(* Logix 5000 project; controller Example_PLC vendor 1 type 14 code 77 rev 19.11; software revision 19.01; part 4 of 6 *)

ADD_ON_INSTRUCTION AKD_Set_Home_Mode   (* revision 2.0, ExecutePrescan, ExecuteEnableInFalse *)
// Set Homing Mode
VAR_OUTPUT
   DN : BOOL; {access Read Only, visible}   // Command Successful
   ER : BOOL; {access Read Only, visible}   // Error
END_VAR
VAR_IN_OUT
   Axis : AKD_Axis; {required}
END_VAR
VAR_INPUT
   Mode : SINT; {required}   // Home Mode:
END_VAR
VAR
   Command_Bytes : SINT[8];
   Step : DINT;
   Set_Attribute : AKD_Set_Attribute;
END_VAR

ROUTINE EnableInFalse   (* ladder *)
// EnableIn_False
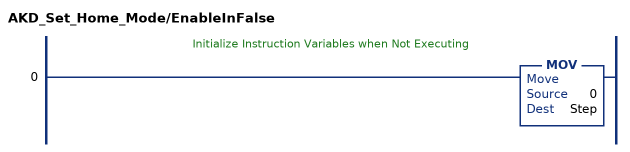
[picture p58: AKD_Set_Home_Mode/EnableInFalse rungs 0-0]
   // Initialize Instruction Variables when Not Executing
   0: MOV(0,Step);
END_ROUTINE

ROUTINE Logic   (* ladder *)
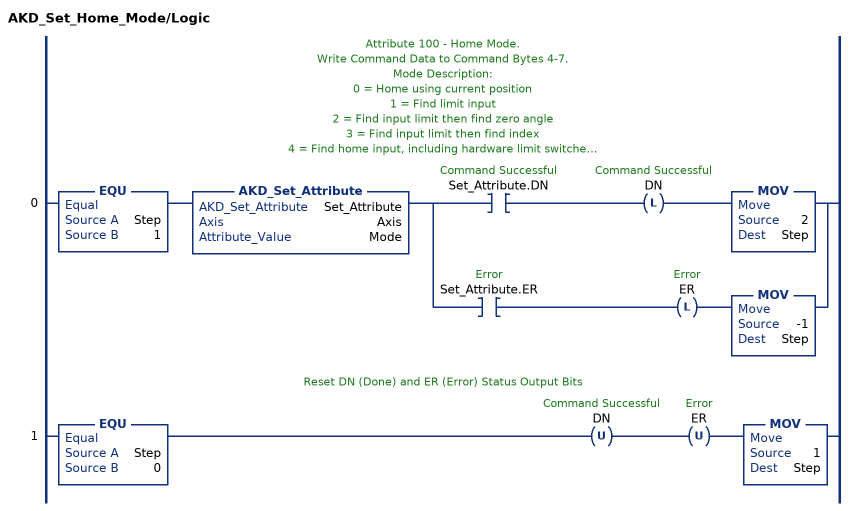
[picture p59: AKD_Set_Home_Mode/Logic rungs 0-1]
   // Attribute 100 - Home Mode.
   // Write Command Data to Command Bytes 4-7.
   // Mode Description:
   // 0 = Home using current position
   // 1 = Find limit input
   // 2 = Find input limit then find zero angle
   // 3 = Find input limit then find index
   // 4 = Find home input, including hardware limit switches
   // 5 = Find home input then find zero angle, including hardware limit switches
   // 6 = Find home input then find index, including hardware limit switches.
   // 7 = Find zero angle
   // 8 = Move until position error exceeded
   // 9 = Move until position error exceeded, then find zero angle
   // 10 = Move until position error exceeded, then find index
   // 11 = Find index signal, without any precondition
   // 12 = Homing to a home-switch, including mechanical stop detection
   0: EQU(Step,1)AKD_Set_Attribute(Set_Attribute,Axis,Mode)[XIC(Set_Attribute.DN) OTL(DN) MOV(2,Step) ,XIC(Set_Attribute.ER) OTL(ER) MOV(-1,Step) ];
   // Reset DN (Done) and ER (Error) Status Output Bits
   1: EQU(Step,0)OTU(DN)OTU(ER)MOV(1,Step);
END_ROUTINE

ROUTINE Prescan   (* ladder *)
// Prescan
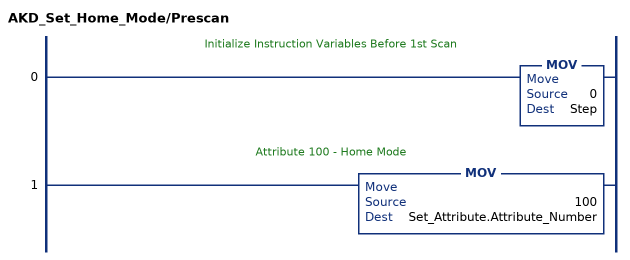
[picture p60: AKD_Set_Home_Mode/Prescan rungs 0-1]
   // Initialize Instruction Variables Before 1st Scan
   0: MOV(0,Step);
   // Attribute 100 - Home Mode
   1: MOV(100,Set_Attribute.Attribute_Number);
END_ROUTINE
END_ADD_ON_INSTRUCTION

ADD_ON_INSTRUCTION AKD_Set_Mode   (* revision 2.2, ExecutePrescan, ExecuteEnableInFalse *)
// Set Drive Mode
// Revision note:
// Recover properly from errors (previously could not recover if AKD_Set_Attribute errored)
VAR_IN_OUT
   Axis : AKD_Axis; {required}
END_VAR
VAR_INPUT
   Mode_Requested : SINT; {required}   // Drive Mode Requested (0=Position, 1=Velocity, 2=Torque)
END_VAR
VAR_OUTPUT
   DN : BOOL; {access Read Only, visible}   // Command Successfully Initiated
   ER : BOOL; {access Read Only, visible}   // Error
   Mode_Actual : SINT; {access Read Only, required}   // Drive Mode Actual (0=Position, 1=Velocity, 2=Torque)
END_VAR
VAR
   Accel_Internal : DINT;   // Scaled Accel Value for Drive
   Step : SINT;   // Sequence Step Number
   ErrorSource : SINT;   // Source of Error
   StartONS : BOOL;
   Pause_Timer : TIMER;   // Pause During Jog Command Sequence
   Get_Mode : AKD_Get_Attribute := (Attribute_Number := 3);
   Set_Mode : AKD_Set_Attribute := (Attribute_Number := 3);
   Command_Timeout : TIMER := (PRE := 100);
END_VAR

ROUTINE EnableInFalse   (* ladder *)
// EnableIn_False
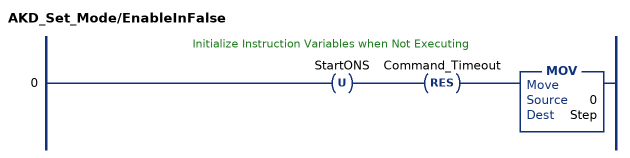
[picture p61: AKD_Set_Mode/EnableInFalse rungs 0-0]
   // Initialize Instruction Variables when Not Executing
   0: OTU(StartONS)RES(Command_Timeout)MOV(0,Step);
END_ROUTINE

ROUTINE Logic   (* ladder *)
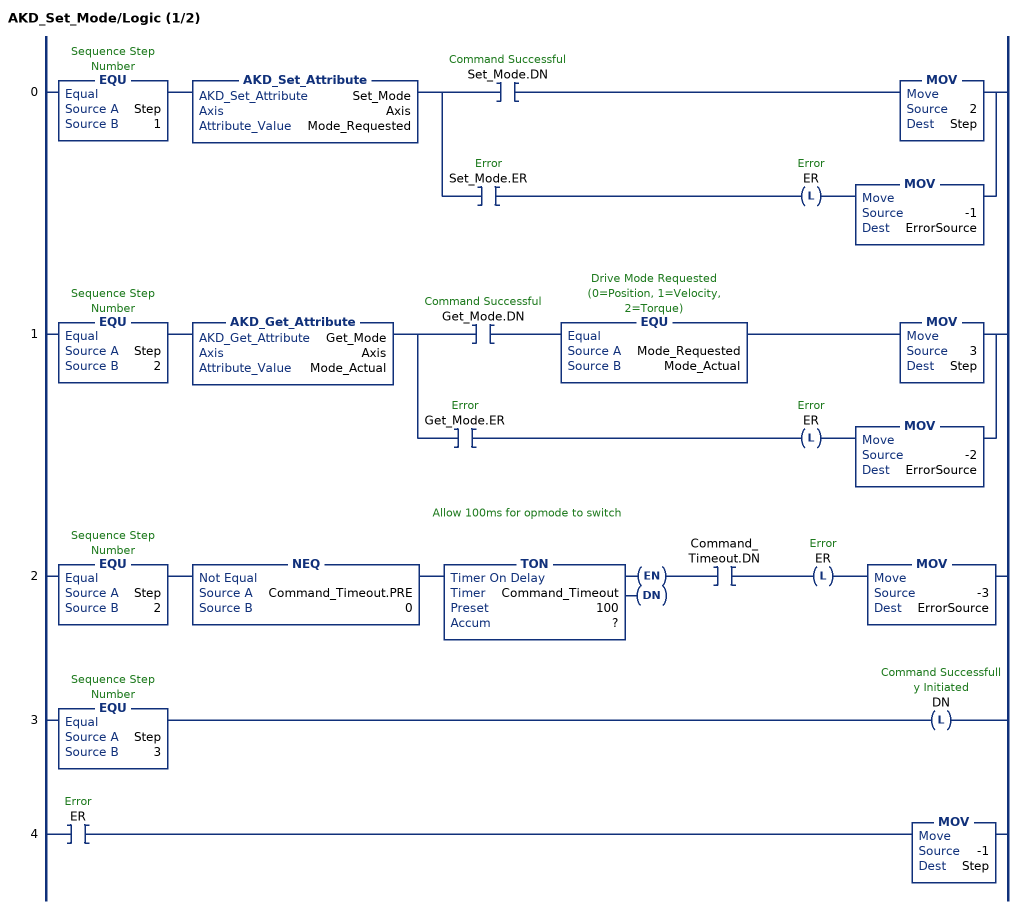
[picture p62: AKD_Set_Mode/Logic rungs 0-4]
   0: EQU(Step,1)AKD_Set_Attribute(Set_Mode,Axis,Mode_Requested)[XIC(Set_Mode.DN) MOV(2,Step) ,XIC(Set_Mode.ER) OTL(ER) MOV(-1,ErrorSource) ];
   1: EQU(Step,2)AKD_Get_Attribute(Get_Mode,Axis,Mode_Actual)[XIC(Get_Mode.DN) EQU(Mode_Requested,Mode_Actual) MOV(3,Step) ,XIC(Get_Mode.ER) OTL(ER) MOV(-2,ErrorSource) ];
   // Allow 100ms for opmode to switch
   2: EQU(Step,2)NEQ(Command_Timeout.PRE,0)TON(Command_Timeout,?,?)XIC(Command_Timeout.DN)OTL(ER)MOV(-3,ErrorSource);
   3: EQU(Step,3)OTL(DN);
   4: XIC(ER)MOV(-1,Step);
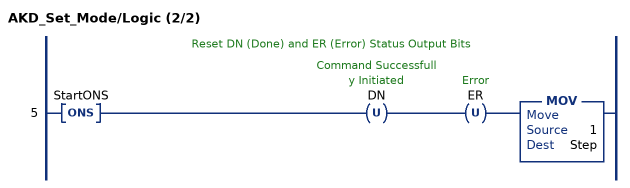
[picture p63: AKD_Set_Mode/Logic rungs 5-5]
   // Reset DN (Done) and ER (Error) Status Output Bits
   5: ONS(StartONS)OTU(DN)OTU(ER)MOV(1,Step);
END_ROUTINE

ROUTINE Prescan   (* ladder *)
// Prescan
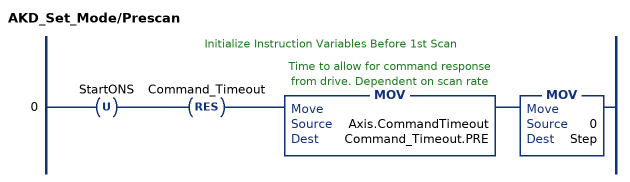
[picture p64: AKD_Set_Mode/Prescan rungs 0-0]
   // Initialize Instruction Variables Before 1st Scan
   0: OTU(StartONS)RES(Command_Timeout)MOV(Axis.CommandTimeout,Command_Timeout.PRE)MOV(0,Step);
END_ROUTINE
END_ADD_ON_INSTRUCTION

ADD_ON_INSTRUCTION AKD_Set_Parameter   (* revision 2.0, ExecutePrescan, ExecuteEnableInFalse *)
// Set Drive Parameter
VAR_OUTPUT
   DN : BOOL; {access Read Only, visible}   // Command Successful
   ER : BOOL; {access Read Only, visible}   // Error
END_VAR
VAR_IN_OUT
   Axis : AKD_Axis; {required}
END_VAR
VAR_INPUT
   Parameter_Number : INT; {visible}   // See help (F1) for parameter list.
   Parameter_Value : DINT; {required}   // Parameter Value
END_VAR
VAR
   Command_Timeout : TIMER := (PRE := 10000);   // Timeout Timer
   Command_Message_Type : SINT;   // Command Message Type
   Command_Axis_Number : SINT;   // Command Axis Number
   Step : SINT;
   Command_Bytes : SINT[8];
   OS_LoadStart : BOOL;
   Temp_Bytes : SINT[2];   // Temporary Bytes to Split into Command Bytes
END_VAR

ROUTINE EnableInFalse   (* ladder *)
// EnableIn_False
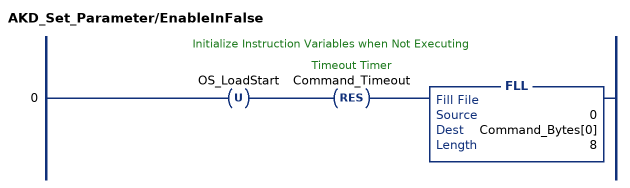
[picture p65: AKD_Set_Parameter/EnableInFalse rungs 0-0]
   // Initialize Instruction Variables when Not Executing
   0: OTU(OS_LoadStart)RES(Command_Timeout)FLL(0,Command_Bytes[0],8);
END_ROUTINE

ROUTINE Logic   (* ladder *)
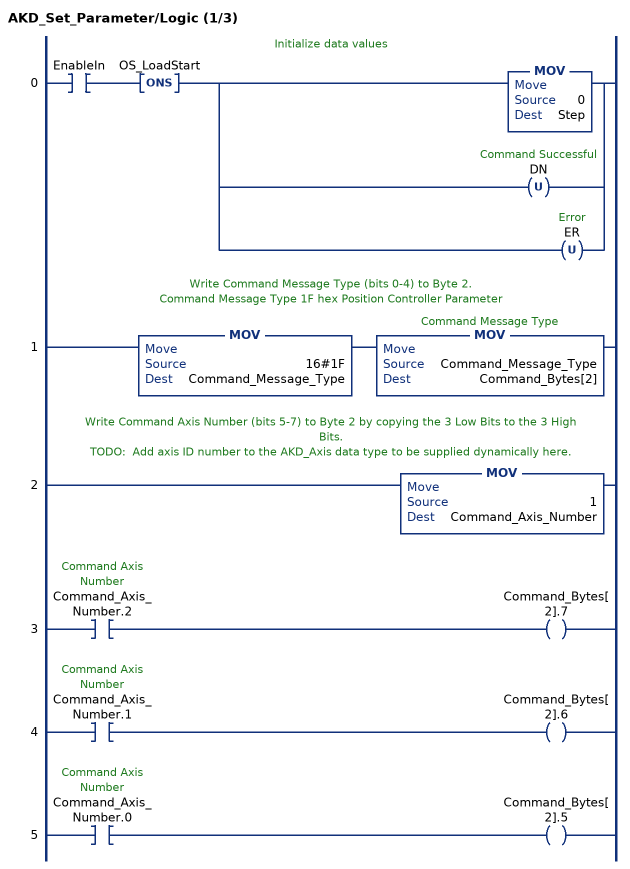
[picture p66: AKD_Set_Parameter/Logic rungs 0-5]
   // Initialize data values
   0: XIC(EnableIn)ONS(OS_LoadStart)[MOV(0,Step) ,OTU(DN) ,OTU(ER) ];
   // Write Command Message Type (bits 0-4) to Byte 2.
   // Command Message Type 1F hex Position Controller Parameter
   1: MOV(16#1F,Command_Message_Type)MOV(Command_Message_Type,Command_Bytes[2]);
   // Write Command Axis Number (bits 5-7) to Byte 2 by copying the 3 Low Bits to the 3 High Bits.
   // TODO:  Add axis ID number to the AKD_Axis data type to be supplied dynamically here.
   2: MOV(1,Command_Axis_Number);
   3: XIC(Command_Axis_Number.2)OTE(Command_Bytes[2].7);
   4: XIC(Command_Axis_Number.1)OTE(Command_Bytes[2].6);
   5: XIC(Command_Axis_Number.0)OTE(Command_Bytes[2].5);
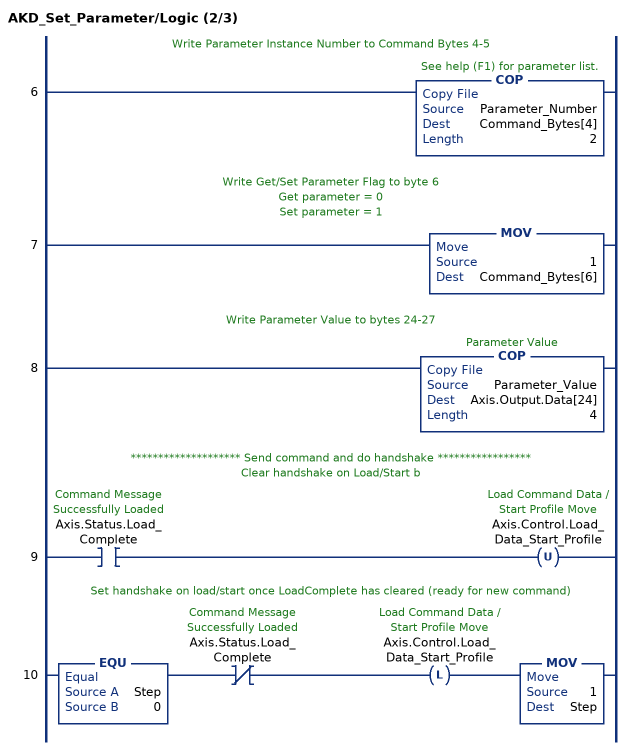
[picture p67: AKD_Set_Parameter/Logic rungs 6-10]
   // Write Parameter Instance Number to Command Bytes 4-5
   6: COP(Parameter_Number,Command_Bytes[4],2);
   // Write Get/Set Parameter Flag to byte 6
   // Get parameter = 0
   // Set parameter = 1
   7: MOV(1,Command_Bytes[6]);
   // Write Parameter Value to bytes 24-27
   8: COP(Parameter_Value,Axis.Output.Data[24],4);
   // ******************** Send command and do handshake *****************
   // Clear handshake on Load/Start b
   9: XIC(Axis.Status.Load_Complete)OTU(Axis.Control.Load_Data_Start_Profile);
   // Set handshake on load/start once LoadComplete has cleared (ready for new command)
   10: EQU(Step,0)XIO(Axis.Status.Load_Complete)OTL(Axis.Control.Load_Data_Start_Profile)MOV(1,Step);
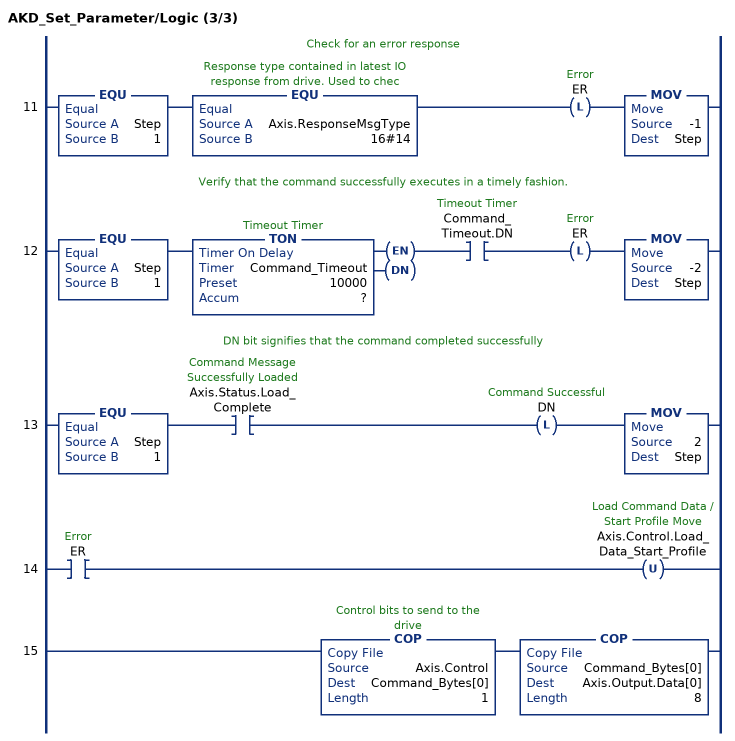
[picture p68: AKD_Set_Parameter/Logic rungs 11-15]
   // Check for an error response
   11: EQU(Step,1)EQU(Axis.ResponseMsgType,16#14)OTL(ER)MOV(-1,Step);
   // Verify that the command successfully executes in a timely fashion.
   12: EQU(Step,1)TON(Command_Timeout,?,?)XIC(Command_Timeout.DN)OTL(ER)MOV(-2,Step);
   // DN bit signifies that the command completed successfully
   13: EQU(Step,1)XIC(Axis.Status.Load_Complete)OTL(DN)MOV(2,Step);
   14: XIC(ER)OTU(Axis.Control.Load_Data_Start_Profile);
   15: COP(Axis.Control,Command_Bytes[0],1)COP(Command_Bytes[0],Axis.Output.Data[0],8);
END_ROUTINE

ROUTINE Prescan   (* ladder *)
// Prescan
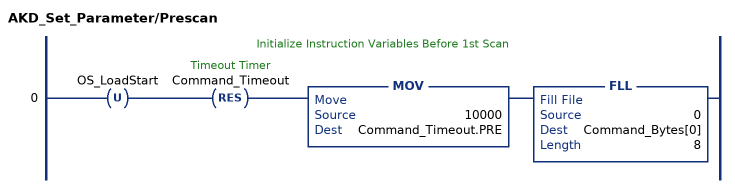
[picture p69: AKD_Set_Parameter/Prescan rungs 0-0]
   // Initialize Instruction Variables Before 1st Scan
   0: OTU(OS_LoadStart)RES(Command_Timeout)MOV(10000,Command_Timeout.PRE)FLL(0,Command_Bytes[0],8);
END_ROUTINE
END_ADD_ON_INSTRUCTION

ADD_ON_INSTRUCTION AKD_Set_Position   (* revision 2.1, ExecutePrescan, ExecuteEnableInFalse *)
// Set Drive Position
// Revision note:
// Don't error if Command_Timeout preset is 0
VAR_OUTPUT
   DN : BOOL; {access Read Only, visible}   // Command Successful
   ER : BOOL; {access Read Only, visible}   // Error
END_VAR
VAR_IN_OUT
   Axis : AKD_Axis; {required}
END_VAR
VAR_INPUT
   Incremental : BOOL; {visible}   // Position Definition (0=Absolute, 1=Incremental)
   Position : DINT; {required}   // Position Value
END_VAR
VAR_OUTPUT
   PC : BOOL; {access Read Only, visible}   // Process Complete
   IP : BOOL; {access Read Only, visible}   // In Process
END_VAR
VAR
   Response_Bytes : SINT[8];
   OS_LoadStart : BOOL;
   Position_Internal : DINT;   // Scaled Position Value for Drive
   Command_Timeout : TIMER := (PRE := 200);   // Timeout Timer
   Command_Message_Type : SINT;   // Command Message Type
   Command_Axis_Number : SINT;   // Command Axis Number
   Response_Message_Type : SINT;   // Response Message Type
   Response_Axis_Number : SINT;   // Response Axis Number
   Command_Bytes : SINT[8];
   Step : SINT;
END_VAR

ROUTINE EnableInFalse   (* ladder *)
// EnableIn_False
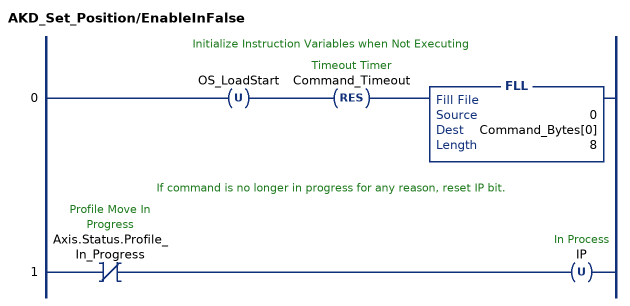
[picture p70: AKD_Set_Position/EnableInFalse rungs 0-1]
   // Initialize Instruction Variables when Not Executing
   0: OTU(OS_LoadStart)RES(Command_Timeout)FLL(0,Command_Bytes[0],8);
   // If command is no longer in progress for any reason, reset IP bit.
   1: XIO(Axis.Status.Profile_In_Progress)OTU(IP);
END_ROUTINE

ROUTINE Logic   (* ladder *)
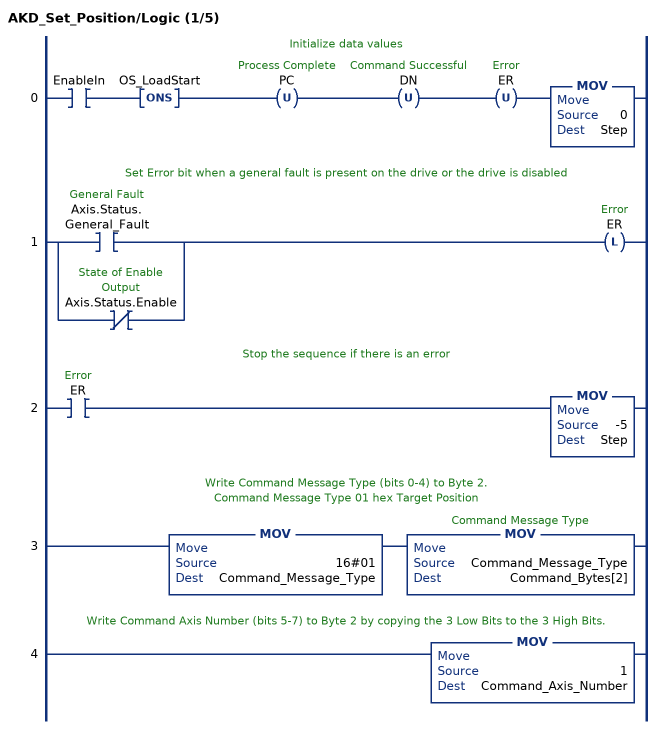
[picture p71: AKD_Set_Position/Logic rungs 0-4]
   // Initialize data values
   0: XIC(EnableIn)ONS(OS_LoadStart)OTU(PC)OTU(DN)OTU(ER)MOV(0,Step);
   // Set Error bit when a general fault is present on the drive or the drive is disabled
   1: [XIC(Axis.Status.General_Fault) ,XIO(Axis.Status.Enable) ]OTL(ER);
   // Stop the sequence if there is an error
   2: XIC(ER)MOV(-5,Step);
   // Write Command Message Type (bits 0-4) to Byte 2.
   // Command Message Type 01 hex Target Position
   3: MOV(16#01,Command_Message_Type)MOV(Command_Message_Type,Command_Bytes[2]);
   // Write Command Axis Number (bits 5-7) to Byte 2 by copying the 3 Low Bits to the 3 High Bits.
   4: MOV(1,Command_Axis_Number);
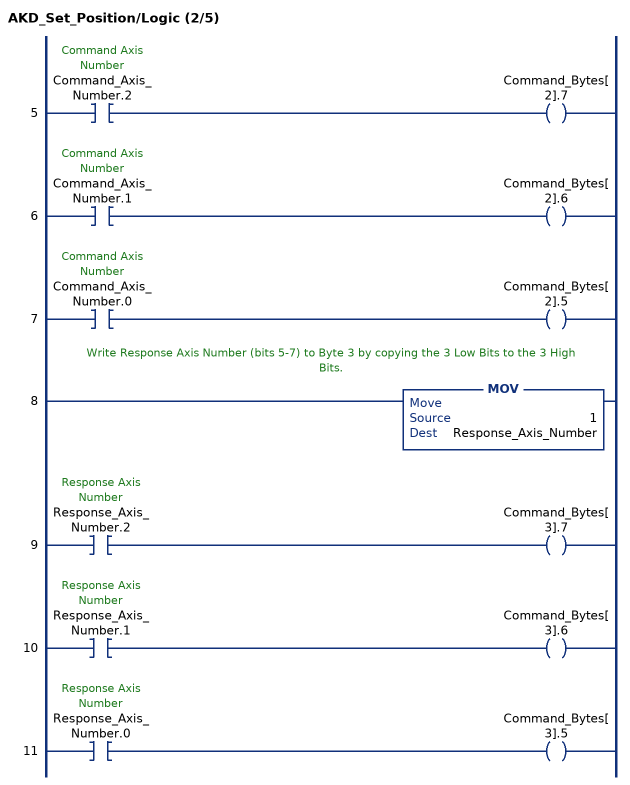
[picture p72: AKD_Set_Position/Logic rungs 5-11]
   5: XIC(Command_Axis_Number.2)OTE(Command_Bytes[2].7);
   6: XIC(Command_Axis_Number.1)OTE(Command_Bytes[2].6);
   7: XIC(Command_Axis_Number.0)OTE(Command_Bytes[2].5);
   // Write Response Axis Number (bits 5-7) to Byte 3 by copying the 3 Low Bits to the 3 High Bits.
   8: MOV(1,Response_Axis_Number);
   9: XIC(Response_Axis_Number.2)OTE(Command_Bytes[3].7);
   10: XIC(Response_Axis_Number.1)OTE(Command_Bytes[3].6);
   11: XIC(Response_Axis_Number.0)OTE(Command_Bytes[3].5);
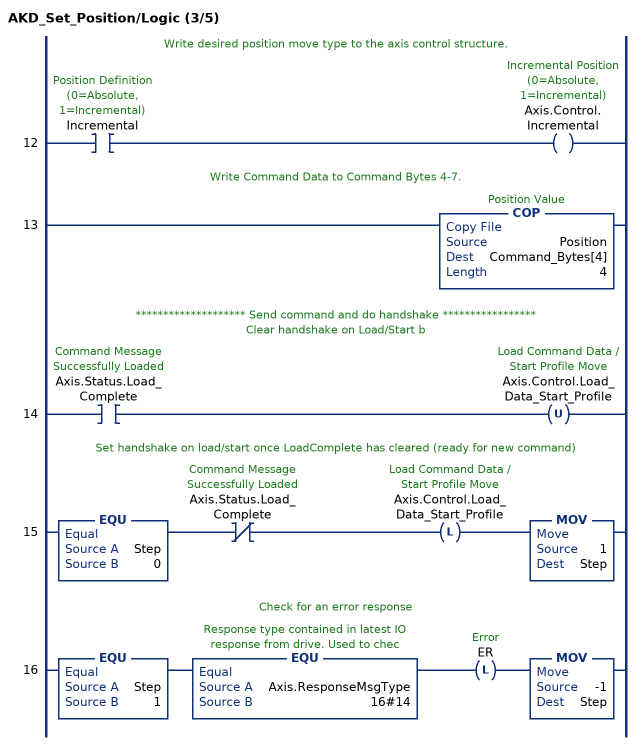
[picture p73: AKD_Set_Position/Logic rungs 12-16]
   // Write desired position move type to the axis control structure.
   12: XIC(Incremental)OTE(Axis.Control.Incremental);
   // Write Command Data to Command Bytes 4-7.
   13: COP(Position,Command_Bytes[4],4);
   // ******************** Send command and do handshake *****************
   // Clear handshake on Load/Start b
   14: XIC(Axis.Status.Load_Complete)OTU(Axis.Control.Load_Data_Start_Profile);
   // Set handshake on load/start once LoadComplete has cleared (ready for new command)
   15: EQU(Step,0)XIO(Axis.Status.Load_Complete)OTL(Axis.Control.Load_Data_Start_Profile)MOV(1,Step);
   // Check for an error response
   16: EQU(Step,1)EQU(Axis.ResponseMsgType,16#14)OTL(ER)MOV(-1,Step);
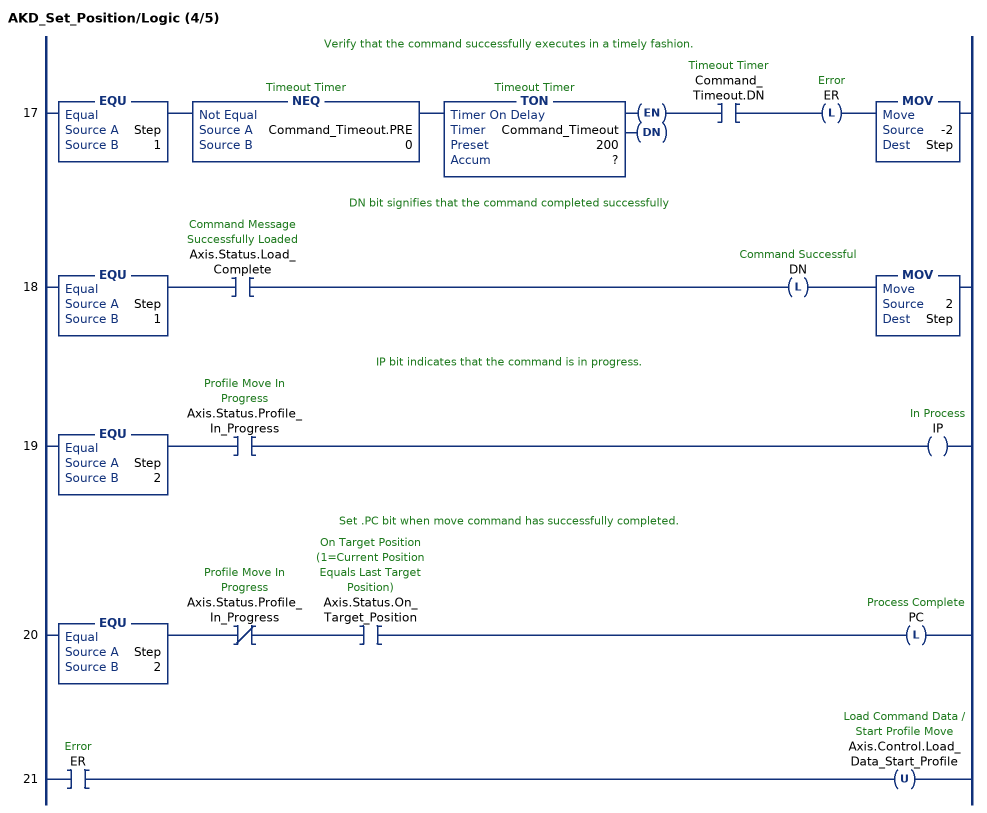
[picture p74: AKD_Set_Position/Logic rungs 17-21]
   // Verify that the command successfully executes in a timely fashion.
   17: EQU(Step,1)NEQ(Command_Timeout.PRE,0)TON(Command_Timeout,?,?)XIC(Command_Timeout.DN)OTL(ER)MOV(-2,Step);
   // DN bit signifies that the command completed successfully
   18: EQU(Step,1)XIC(Axis.Status.Load_Complete)OTL(DN)MOV(2,Step);
   // IP bit indicates that the command is in progress.
   19: EQU(Step,2)XIC(Axis.Status.Profile_In_Progress)OTE(IP);
   // Set .PC bit when move command has successfully completed.
   20: EQU(Step,2)XIO(Axis.Status.Profile_In_Progress)XIC(Axis.Status.On_Target_Position)OTL(PC);
   21: XIC(ER)OTU(Axis.Control.Load_Data_Start_Profile);
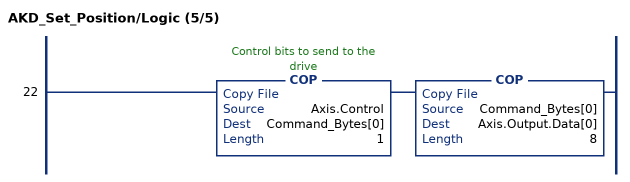
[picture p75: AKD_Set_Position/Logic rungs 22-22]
   22: COP(Axis.Control,Command_Bytes[0],1)COP(Command_Bytes[0],Axis.Output.Data[0],8);
END_ROUTINE
(* Logix 5000 project; controller Example_PLC vendor 1 type 14 code 77 rev 19.11; software revision 19.01; part 5 of 6 *)
(* tags used below, declared in another part *)
   Position : DINT;   // Position Value
(* AKD_Set_Position, continued *)

ROUTINE Prescan   (* ladder *)
// Prescan
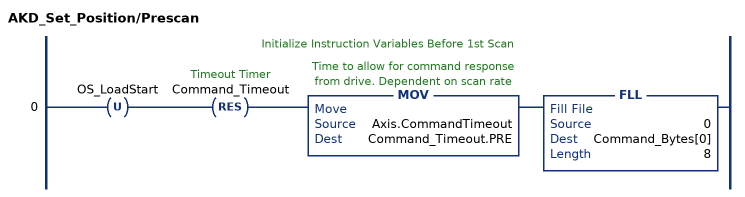
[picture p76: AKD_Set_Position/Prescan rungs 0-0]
   // Initialize Instruction Variables Before 1st Scan
   0: OTU(OS_LoadStart)RES(Command_Timeout)MOV(Axis.CommandTimeout,Command_Timeout.PRE)FLL(0,Command_Bytes[0],8);
END_ROUTINE
END_ADD_ON_INSTRUCTION

ADD_ON_INSTRUCTION AKD_Set_Units   (* revision 2.2, ExecutePrescan, ExecuteEnableInFalse *)
// Set Drive Units for Motion Commands
// Revision note:
// Clean up instruction, especially for error recovery.
VAR_IN_OUT
   Axis : AKD_Axis; {required}
END_VAR
VAR_INPUT
   Units : SINT; {required}   // Drive Units (0=Counts 16 bit)
END_VAR
VAR_OUTPUT
   DN : BOOL; {access Read Only, visible}   // Command Successfully Initiated
   ER : BOOL; {access Read Only, visible}   // Error
END_VAR
VAR
   Set_POSUNIT : AKD_Set_Attribute := (Attribute_Number := 4);
   Set_PROFUNIT : AKD_Set_Attribute := (Attribute_Number := 5);
   Step : SINT;   // Sequence Step Number
   OS_Start_Sequence : BOOL;
   Profile_Ratio : DINT;   // The number of actual feedback counts per second or second2 equal to one velocity or acceleration unit
   Position_Ratio : DINT;   // The number of actual position feedback counts equal to one position unit
   Invalid_Input : BOOL;   // Invalid Units Input
END_VAR

ROUTINE EnableInFalse   (* ladder *)
// EnableIn_False
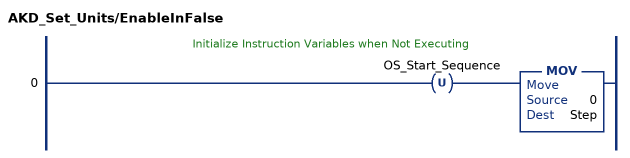
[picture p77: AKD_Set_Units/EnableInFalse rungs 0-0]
   // Initialize Instruction Variables when Not Executing
   0: OTU(OS_Start_Sequence)MOV(0,Step);
END_ROUTINE

ROUTINE Logic   (* ladder *)
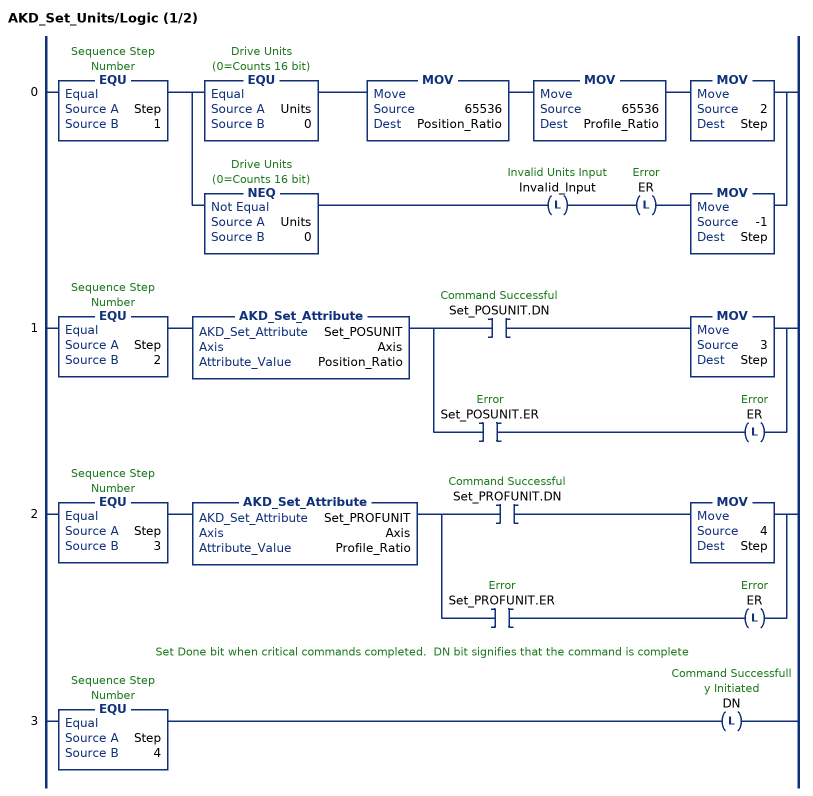
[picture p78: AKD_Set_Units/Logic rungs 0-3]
   0: EQU(Step,1)[EQU(Units,0) MOV(65536,Position_Ratio) MOV(65536,Profile_Ratio) MOV(2,Step) ,NEQ(Units,0) OTL(Invalid_Input) OTL(ER) MOV(-1,Step) ];
   1: EQU(Step,2)AKD_Set_Attribute(Set_POSUNIT,Axis,Position_Ratio)[XIC(Set_POSUNIT.DN) MOV(3,Step) ,XIC(Set_POSUNIT.ER) OTL(ER) ];
   2: EQU(Step,3)AKD_Set_Attribute(Set_PROFUNIT,Axis,Profile_Ratio)[XIC(Set_PROFUNIT.DN) MOV(4,Step) ,XIC(Set_PROFUNIT.ER) OTL(ER) ];
   // Set Done bit when critical commands completed.  DN bit signifies that the command is complete
   3: EQU(Step,4)OTL(DN);
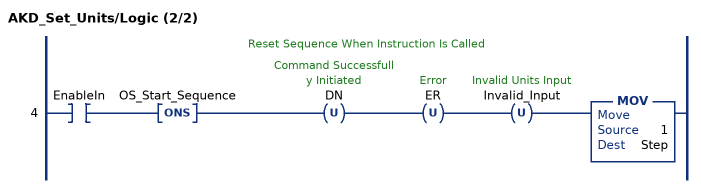
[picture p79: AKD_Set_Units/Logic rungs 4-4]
   // Reset Sequence When Instruction Is Called
   4: XIC(EnableIn)ONS(OS_Start_Sequence)OTU(DN)OTU(ER)OTU(Invalid_Input)MOV(1,Step);
END_ROUTINE

ROUTINE Prescan   (* ladder *)
// Prescan
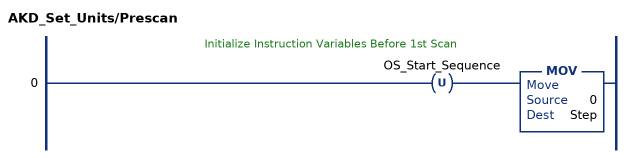
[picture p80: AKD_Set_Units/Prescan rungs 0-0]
   // Initialize Instruction Variables Before 1st Scan
   0: OTU(OS_Start_Sequence)MOV(0,Step);
END_ROUTINE
END_ADD_ON_INSTRUCTION

ADD_ON_INSTRUCTION AKD_Set_Velocity   (* revision 2.1, ExecutePrescan, ExecuteEnableInFalse *)
// Set Drive Velocity
// Revision note:
// Don't error if Command_Timeout preset is 0
VAR_OUTPUT
   DN : BOOL; {access Read Only, visible}   // Command Successful
   ER : BOOL; {access Read Only, visible}   // Error
END_VAR
VAR_IN_OUT
   Axis : AKD_Axis; {required}
END_VAR
VAR_INPUT
   Velocity : DINT; {required}   // Velocity
END_VAR
VAR
   Response_Bytes : SINT[8];
   OS_LoadStart : BOOL;
   Velocity_Internal : DINT;   // Scaled Velocity Value for Drive
   Command_Timeout : TIMER := (PRE := 100);   // Timeout Timer
   Command_Message_Type : SINT;   // Command Message Type
   Command_Axis_Number : SINT;   // Command Axis Number
   Response_Message_Type : SINT;   // Response Message Type
   Response_Axis_Number : SINT;   // Response Axis Number
   Command_Bytes : SINT[8];
   Step : SINT;
END_VAR

ROUTINE EnableInFalse   (* ladder *)
// EnableIn_False
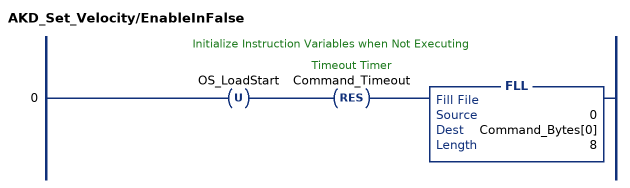
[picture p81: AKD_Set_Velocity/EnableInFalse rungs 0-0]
   // Initialize Instruction Variables when Not Executing
   0: OTU(OS_LoadStart)RES(Command_Timeout)FLL(0,Command_Bytes[0],8);
END_ROUTINE

ROUTINE Logic   (* ladder *)
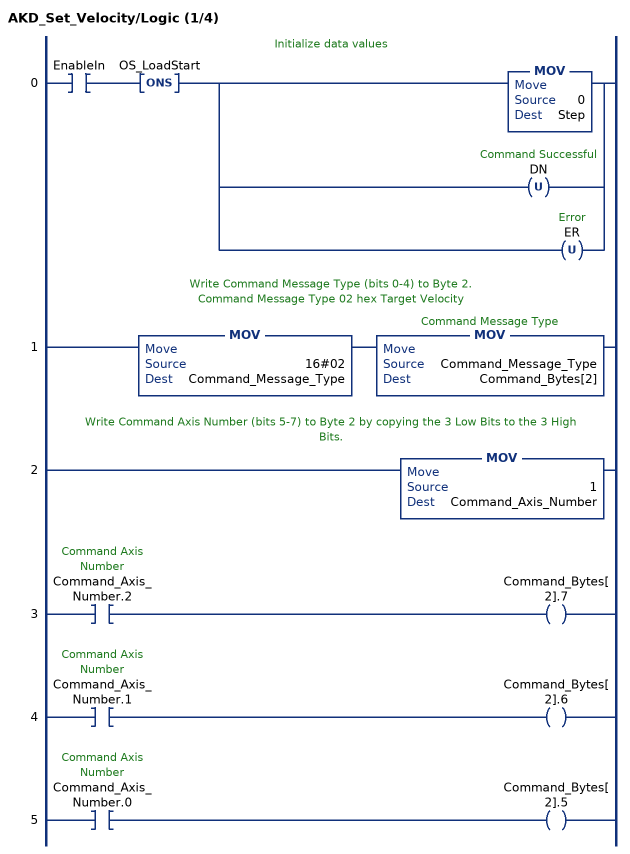
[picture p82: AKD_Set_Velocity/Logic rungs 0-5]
   // Initialize data values
   0: XIC(EnableIn)ONS(OS_LoadStart)[MOV(0,Step) ,OTU(DN) ,OTU(ER) ];
   // Write Command Message Type (bits 0-4) to Byte 2.
   // Command Message Type 02 hex Target Velocity
   1: MOV(16#02,Command_Message_Type)MOV(Command_Message_Type,Command_Bytes[2]);
   // Write Command Axis Number (bits 5-7) to Byte 2 by copying the 3 Low Bits to the 3 High Bits.
   2: MOV(1,Command_Axis_Number);
   3: XIC(Command_Axis_Number.2)OTE(Command_Bytes[2].7);
   4: XIC(Command_Axis_Number.1)OTE(Command_Bytes[2].6);
   5: XIC(Command_Axis_Number.0)OTE(Command_Bytes[2].5);
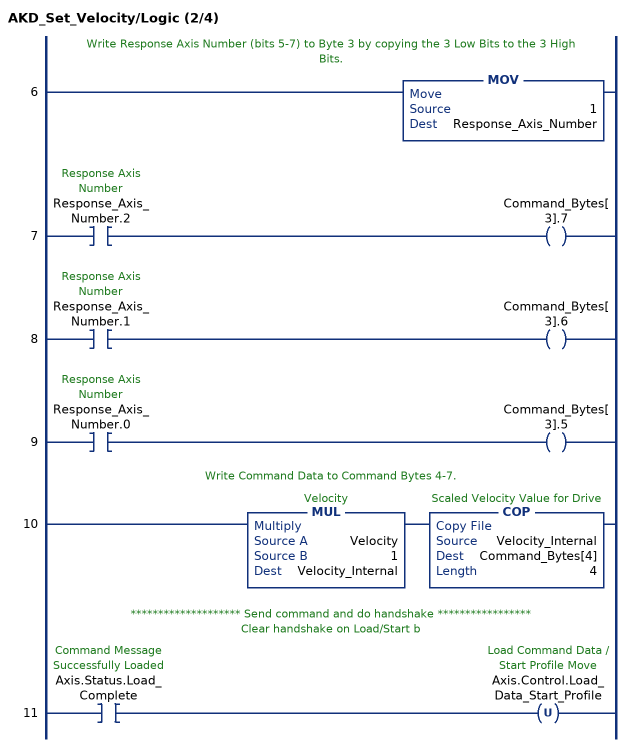
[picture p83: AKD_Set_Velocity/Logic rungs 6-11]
   // Write Response Axis Number (bits 5-7) to Byte 3 by copying the 3 Low Bits to the 3 High Bits.
   6: MOV(1,Response_Axis_Number);
   7: XIC(Response_Axis_Number.2)OTE(Command_Bytes[3].7);
   8: XIC(Response_Axis_Number.1)OTE(Command_Bytes[3].6);
   9: XIC(Response_Axis_Number.0)OTE(Command_Bytes[3].5);
   // Write Command Data to Command Bytes 4-7.
   10: MUL(Velocity,1,Velocity_Internal)COP(Velocity_Internal,Command_Bytes[4],4);
   // ******************** Send command and do handshake *****************
   // Clear handshake on Load/Start b
   11: XIC(Axis.Status.Load_Complete)OTU(Axis.Control.Load_Data_Start_Profile);
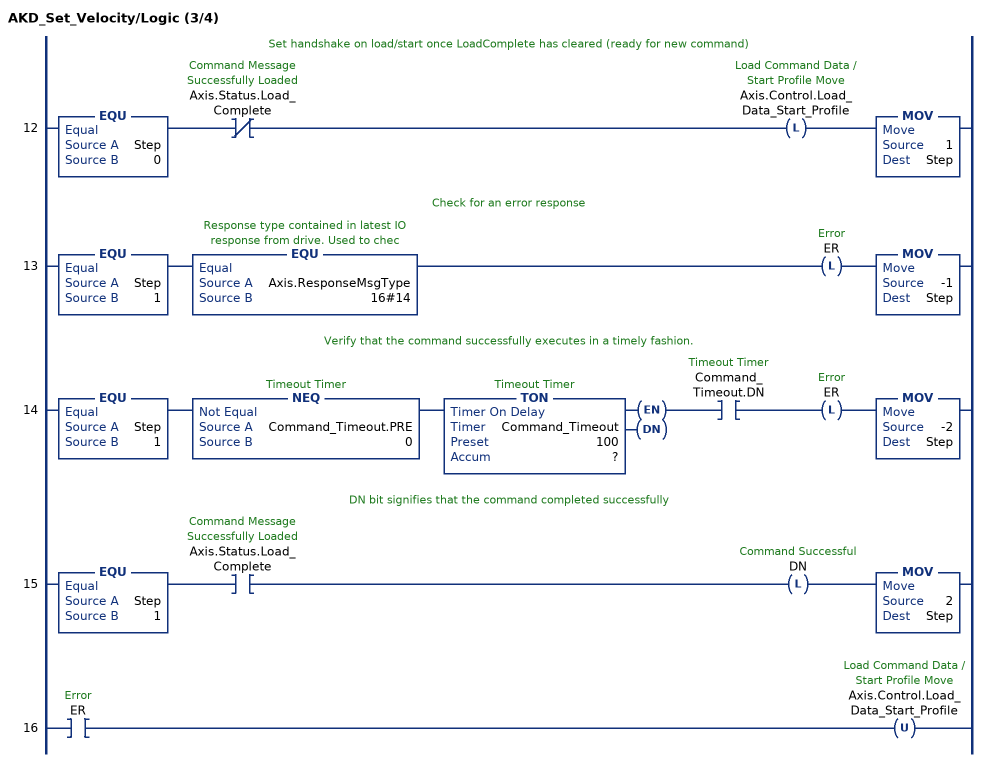
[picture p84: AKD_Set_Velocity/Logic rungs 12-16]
   // Set handshake on load/start once LoadComplete has cleared (ready for new command)
   12: EQU(Step,0)XIO(Axis.Status.Load_Complete)OTL(Axis.Control.Load_Data_Start_Profile)MOV(1,Step);
   // Check for an error response
   13: EQU(Step,1)EQU(Axis.ResponseMsgType,16#14)OTL(ER)MOV(-1,Step);
   // Verify that the command successfully executes in a timely fashion.
   14: EQU(Step,1)NEQ(Command_Timeout.PRE,0)TON(Command_Timeout,?,?)XIC(Command_Timeout.DN)OTL(ER)MOV(-2,Step);
   // DN bit signifies that the command completed successfully
   15: EQU(Step,1)XIC(Axis.Status.Load_Complete)OTL(DN)MOV(2,Step);
   16: XIC(ER)OTU(Axis.Control.Load_Data_Start_Profile);
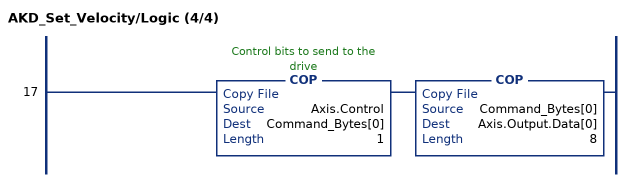
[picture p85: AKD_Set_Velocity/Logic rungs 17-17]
   17: COP(Axis.Control,Command_Bytes[0],1)COP(Command_Bytes[0],Axis.Output.Data[0],8);
END_ROUTINE

ROUTINE Prescan   (* ladder *)
// Prescan
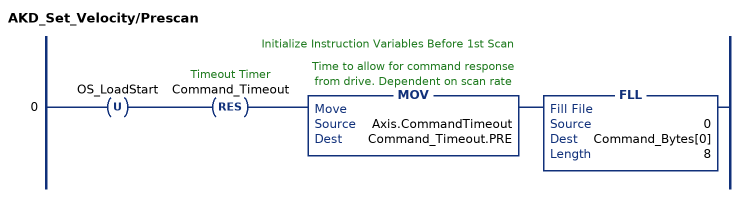
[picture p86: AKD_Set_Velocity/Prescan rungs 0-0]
   // Initialize Instruction Variables Before 1st Scan
   0: OTU(OS_LoadStart)RES(Command_Timeout)MOV(Axis.CommandTimeout,Command_Timeout.PRE)FLL(0,Command_Bytes[0],8);
END_ROUTINE
END_ADD_ON_INSTRUCTION

ADD_ON_INSTRUCTION AKD_Shutdown   (* revision 2.0, ExecutePrescan, ExecuteEnableInFalse *)
// Motion Hard Stop
VAR_OUTPUT
   DN : BOOL; {access Read Only, visible}   // Command Successful
   ER : BOOL; {access Read Only, visible}   // Error
END_VAR
VAR_IN_OUT
   Axis : AKD_Axis; {required}
END_VAR
VAR
   Command_Timeout : TIMER := (PRE := 2000);   // Timeout Timer
END_VAR

ROUTINE EnableInFalse   (* ladder *)
// Enable In False
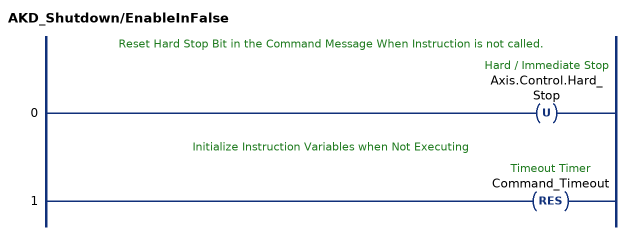
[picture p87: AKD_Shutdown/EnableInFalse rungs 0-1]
   // Reset Hard Stop Bit in the Command Message When Instruction is not called.
   0: OTU(Axis.Control.Hard_Stop);
   // Initialize Instruction Variables when Not Executing
   1: RES(Command_Timeout);
END_ROUTINE

ROUTINE Logic   (* ladder *)
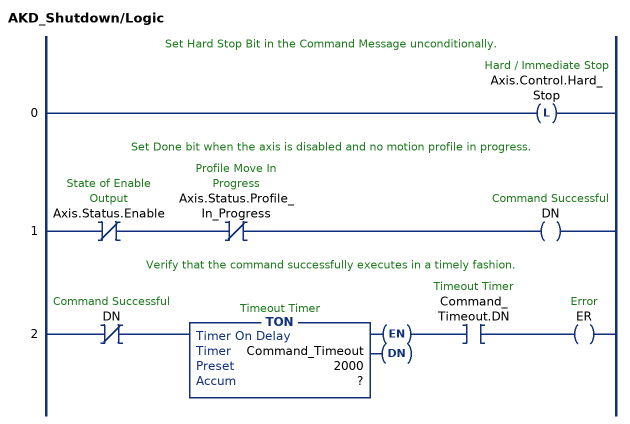
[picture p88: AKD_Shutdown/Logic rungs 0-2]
   // Set Hard Stop Bit in the Command Message unconditionally.
   0: OTL(Axis.Control.Hard_Stop);
   // Set Done bit when the axis is disabled and no motion profile in progress.
   1: XIO(Axis.Status.Enable)XIO(Axis.Status.Profile_In_Progress)OTE(DN);
   // Verify that the command successfully executes in a timely fashion.
   2: XIO(DN)TON(Command_Timeout,?,?)XIC(Command_Timeout.DN)OTE(ER);
END_ROUTINE

ROUTINE Prescan   (* ladder *)
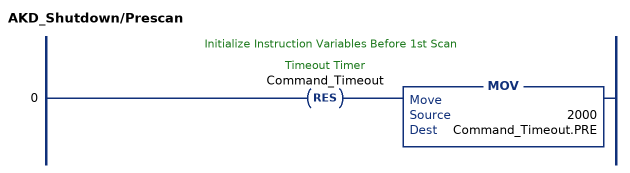
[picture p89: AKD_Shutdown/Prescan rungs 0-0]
   // Initialize Instruction Variables Before 1st Scan
   0: RES(Command_Timeout)MOV(2000,Command_Timeout.PRE);
END_ROUTINE
END_ADD_ON_INSTRUCTION

ADD_ON_INSTRUCTION AKD_Stop_Smooth   (* revision 2.3, ExecutePrescan, ExecuteEnableInFalse *)
// Motion Smooth Stop
// Revision note:
// Remove the command timeout (allow unlimited time to stop). Add an IP In Progress bit which is active while stopping.
VAR_OUTPUT
   DN : BOOL; {access Read Only, visible}   // Command Successful
   ER : BOOL; {access Read Only, visible}   // Error
END_VAR
VAR_IN_OUT
   Axis : AKD_Axis; {required}
END_VAR
VAR_OUTPUT
   IP : BOOL; {access Read Only, visible}   // In Progress
END_VAR

ROUTINE EnableInFalse   (* ladder *)
// Enable In False
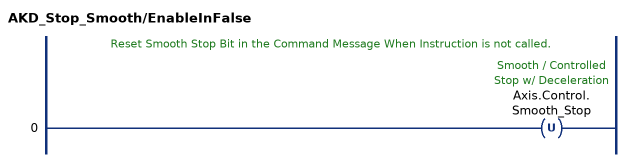
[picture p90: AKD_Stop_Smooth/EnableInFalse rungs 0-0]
   // Reset Smooth Stop Bit in the Command Message When Instruction is not called.
   0: OTU(Axis.Control.Smooth_Stop);
END_ROUTINE

ROUTINE Logic   (* ladder *)
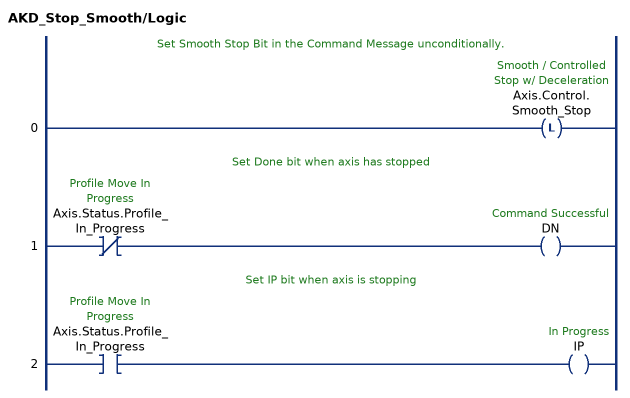
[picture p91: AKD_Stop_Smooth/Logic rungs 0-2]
   // Set Smooth Stop Bit in the Command Message unconditionally.
   0: OTL(Axis.Control.Smooth_Stop);
   // Set Done bit when axis has stopped
   1: XIO(Axis.Status.Profile_In_Progress)OTE(DN);
   // Set IP bit when axis is stopping
   2: XIC(Axis.Status.Profile_In_Progress)OTE(IP);
END_ROUTINE

ROUTINE Prescan   (* ladder *)
END_ROUTINE
END_ADD_ON_INSTRUCTION

ADD_ON_INSTRUCTION AKD_Torque_Move   (* revision 2.1, ExecutePrescan, ExecuteEnableInFalse *)
// Set Torque Command
VAR_OUTPUT
   DN : BOOL; {access Read Only, visible}   // Command Successful
   ER : BOOL; {access Read Only, visible}   // Error
END_VAR
VAR_IN_OUT
   Axis : AKD_Axis; {required}
END_VAR
VAR_INPUT
   Torque : DINT; {required}   // Torque Command
END_VAR
VAR
   Response_Bytes : SINT[8];
   OS_LoadStart : BOOL;
   Command_Timeout : TIMER := (PRE := 100);   // Timeout Timer
   Command_Message_Type : SINT;   // Command Message Type
   Command_Axis_Number : SINT;   // Command Axis Number
   Response_Message_Type : SINT;   // Response Message Type
   Response_Axis_Number : SINT;   // Response Axis Number
   Command_Bytes : SINT[8];
   Step : SINT;
END_VAR

ROUTINE EnableInFalse   (* ladder *)
// EnableIn_False
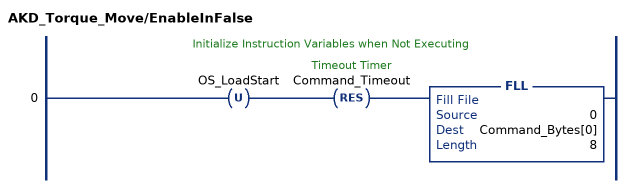
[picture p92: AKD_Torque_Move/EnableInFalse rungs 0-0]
   // Initialize Instruction Variables when Not Executing
   0: OTU(OS_LoadStart)RES(Command_Timeout)FLL(0,Command_Bytes[0],8);
END_ROUTINE

ROUTINE Logic   (* ladder *)
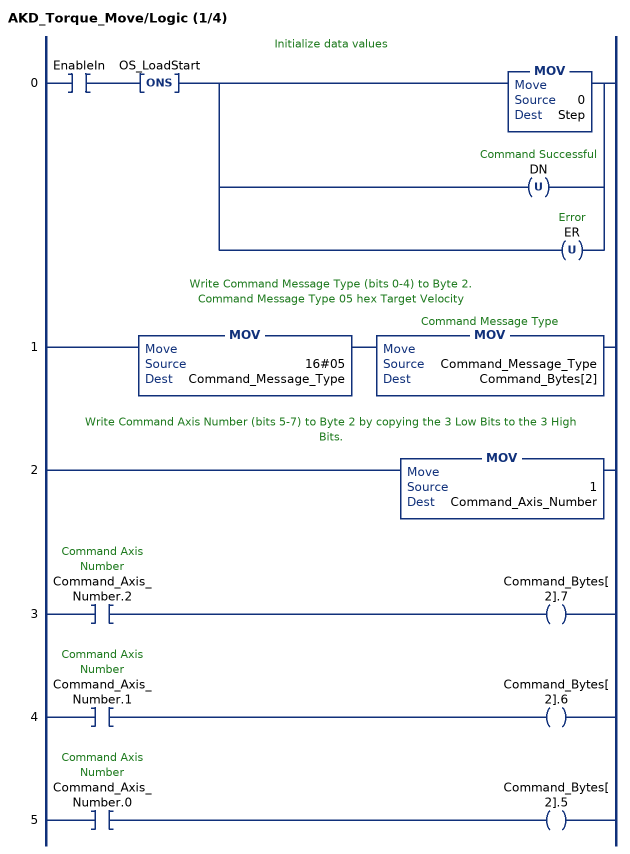
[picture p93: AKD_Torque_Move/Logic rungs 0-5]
   // Initialize data values
   0: XIC(EnableIn)ONS(OS_LoadStart)[MOV(0,Step) ,OTU(DN) ,OTU(ER) ];
   // Write Command Message Type (bits 0-4) to Byte 2.
   // Command Message Type 05 hex Target Velocity
   1: MOV(16#05,Command_Message_Type)MOV(Command_Message_Type,Command_Bytes[2]);
   // Write Command Axis Number (bits 5-7) to Byte 2 by copying the 3 Low Bits to the 3 High Bits.
   2: MOV(1,Command_Axis_Number);
   3: XIC(Command_Axis_Number.2)OTE(Command_Bytes[2].7);
   4: XIC(Command_Axis_Number.1)OTE(Command_Bytes[2].6);
   5: XIC(Command_Axis_Number.0)OTE(Command_Bytes[2].5);
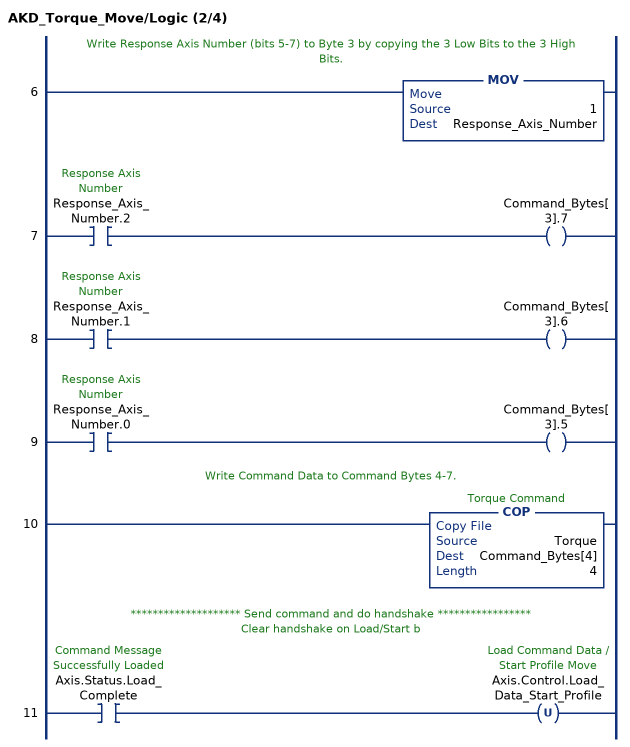
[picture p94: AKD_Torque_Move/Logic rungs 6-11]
   // Write Response Axis Number (bits 5-7) to Byte 3 by copying the 3 Low Bits to the 3 High Bits.
   6: MOV(1,Response_Axis_Number);
   7: XIC(Response_Axis_Number.2)OTE(Command_Bytes[3].7);
   8: XIC(Response_Axis_Number.1)OTE(Command_Bytes[3].6);
   9: XIC(Response_Axis_Number.0)OTE(Command_Bytes[3].5);
   // Write Command Data to Command Bytes 4-7.
   10: COP(Torque,Command_Bytes[4],4);
   // ******************** Send command and do handshake *****************
   // Clear handshake on Load/Start b
   11: XIC(Axis.Status.Load_Complete)OTU(Axis.Control.Load_Data_Start_Profile);
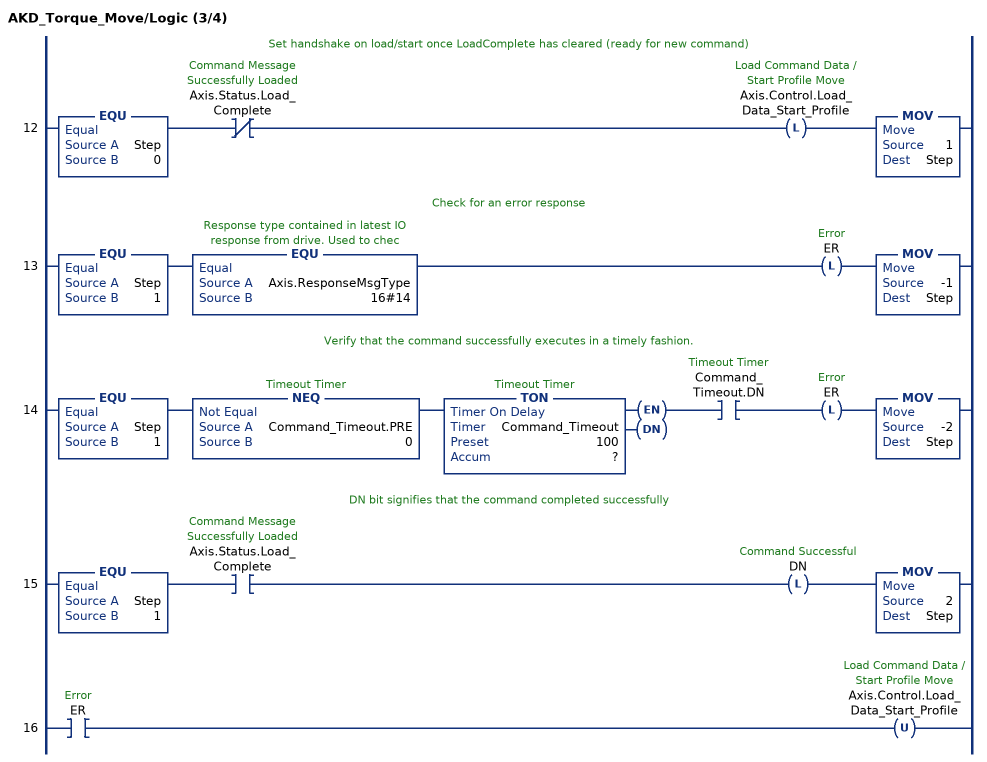
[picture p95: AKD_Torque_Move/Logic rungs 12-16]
   // Set handshake on load/start once LoadComplete has cleared (ready for new command)
   12: EQU(Step,0)XIO(Axis.Status.Load_Complete)OTL(Axis.Control.Load_Data_Start_Profile)MOV(1,Step);
   // Check for an error response
   13: EQU(Step,1)EQU(Axis.ResponseMsgType,16#14)OTL(ER)MOV(-1,Step);
   // Verify that the command successfully executes in a timely fashion.
   14: EQU(Step,1)NEQ(Command_Timeout.PRE,0)TON(Command_Timeout,?,?)XIC(Command_Timeout.DN)OTL(ER)MOV(-2,Step);
   // DN bit signifies that the command completed successfully
   15: EQU(Step,1)XIC(Axis.Status.Load_Complete)OTL(DN)MOV(2,Step);
   16: XIC(ER)OTU(Axis.Control.Load_Data_Start_Profile);
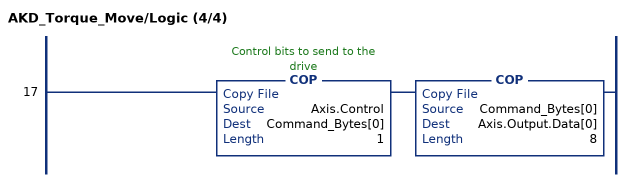
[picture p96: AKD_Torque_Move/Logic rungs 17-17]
   17: COP(Axis.Control,Command_Bytes[0],1)COP(Command_Bytes[0],Axis.Output.Data[0],8);
END_ROUTINE
(* Logix 5000 project; controller Example_PLC vendor 1 type 14 code 77 rev 19.11; software revision 19.01; part 6 of 6 *)
(* tags used below, declared in another part *)
   Axis : AKD_Axis;
   OS_LoadStart : BOOL;
   Command_Timeout : TIMER;   // Timeout Timer
   Command_Bytes : SINT[8];
(* AKD_Torque_Move, continued *)

ROUTINE Prescan   (* ladder *)
// Prescan
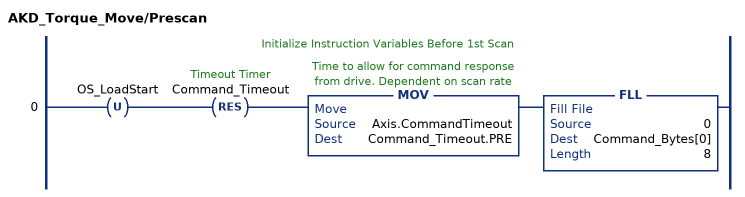
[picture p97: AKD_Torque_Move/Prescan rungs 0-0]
   // Initialize Instruction Variables Before 1st Scan
   0: OTU(OS_LoadStart)RES(Command_Timeout)MOV(Axis.CommandTimeout,Command_Timeout.PRE)FLL(0,Command_Bytes[0],8);
END_ROUTINE
END_ADD_ON_INSTRUCTION

VAR_GLOBAL   (* controller tags *)
   AIN_VALUE : DINT := 7047;
   AKD_1 : AKD_Drive;
   AOUT : DINT;
   AOUT_VALUEU : LINT;
   Axis_1 : AKD_Drive;
   AXIS_ONE : AKD_Axis := (Status.Current_Direction := 1, Input.Data[0] := 16, Input.Data[8] := -6, Input.Data[9] := 78, Input.Data[12] := -19, Input.Data[13] := 10, PositionFeedback := 20218, VelocityFeedback := 2797);
   DIN1_STATE : BOOL;
   DM_EN_SET : BOOL := 1;
   DOUT_STATEU : BOOL;
   Dynamic : BOOL;
   EN : BOOL;
   OneShot : BOOL;
   Start_Dynamic_data_transfer : BOOL;
   Start_Dynamic_mapped_Data : BOOL;
END_VAR

PROGRAM MainProgram   (* main routine MainRoutine *)

ROUTINE MainRoutine   (* ladder *)
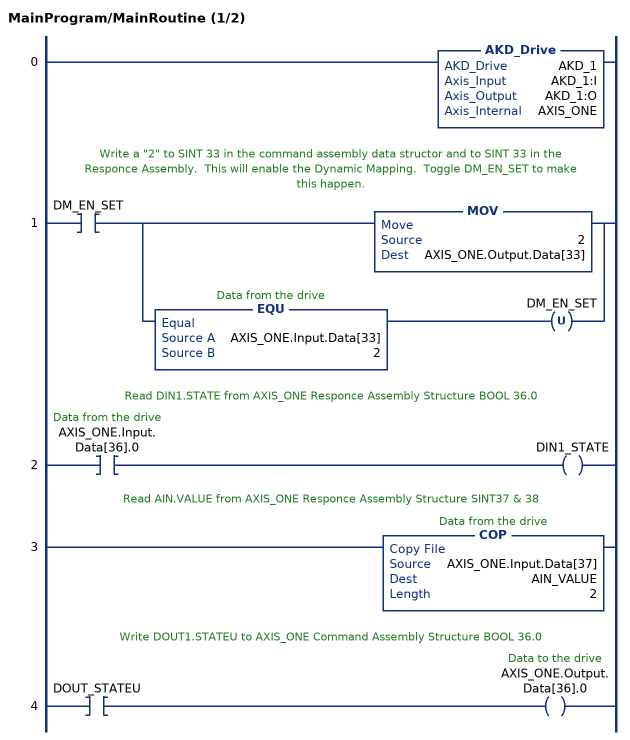
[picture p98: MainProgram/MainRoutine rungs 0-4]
   0: AKD_Drive(AKD_1,AKD_1:I,AKD_1:O,AXIS_ONE);
   // Write a "2" to SINT 33 in the command assembly data structor and to SINT 33 in the Responce Assembly.  This will enable the Dynamic Mapping.  Toggle DM_EN_SET to make this happen.
   1: XIC(DM_EN_SET)[MOV(2,AXIS_ONE.Output.Data[33]) ,EQU(AXIS_ONE.Input.Data[33],2) OTU(DM_EN_SET) ];
   // Read DIN1.STATE from AXIS_ONE Responce Assembly Structure BOOL 36.0
   2: XIC(AXIS_ONE.Input.Data[36].0)OTE(DIN1_STATE);
   // Read AIN.VALUE from AXIS_ONE Responce Assembly Structure SINT37 & 38
   3: COP(AXIS_ONE.Input.Data[37],AIN_VALUE,2);
   // Write DOUT1.STATEU to AXIS_ONE Command Assembly Structure BOOL 36.0
   4: XIC(DOUT_STATEU)OTE(AXIS_ONE.Output.Data[36].0);
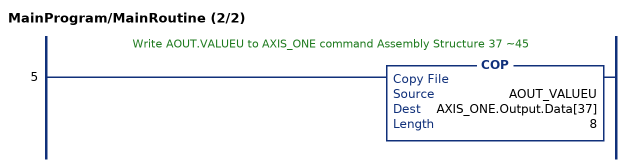
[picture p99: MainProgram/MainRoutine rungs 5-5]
   // Write AOUT.VALUEU to AXIS_ONE command Assembly Structure 37 ~45
   5: COP(AOUT_VALUEU,AXIS_ONE.Output.Data[37],8);
END_ROUTINE
END_PROGRAM
